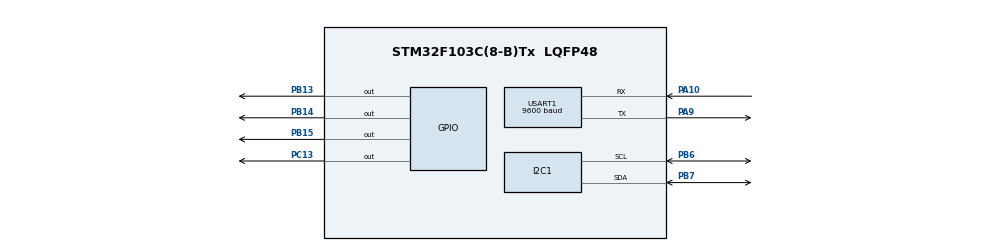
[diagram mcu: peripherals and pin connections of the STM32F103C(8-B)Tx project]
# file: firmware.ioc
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Mcu.Family=STM32F1
Mcu.Name=STM32F103C(8-B)Tx
Mcu.Package=LQFP48
NVIC.PriorityGroup=NVIC_PRIORITYGROUP_4
PA10.Mode=Asynchronous
PA10.Signal=USART1_RX
PA13.Mode=Serial_Wire
PA13.Signal=SYS_JTMS-SWDIO
PA14.Mode=Serial_Wire
PA14.Signal=SYS_JTCK-SWCLK
PA9.Mode=Asynchronous
PA9.Signal=USART1_TX
PB13.Signal=GPIO_Output
PB14.Signal=GPIO_Output
PB15.Signal=GPIO_Output
PB6.Mode=I2C
PB6.Signal=I2C1_SCL
PB7.Mode=I2C
PB7.Signal=I2C1_SDA
PC13-TAMPER-RTC.Signal=GPIO_Output
PC14-OSC32_IN.Mode=LSE-External-Oscillator
PC14-OSC32_IN.Signal=RCC_OSC32_IN
PC15-OSC32_OUT.Mode=LSE-External-Oscillator
PC15-OSC32_OUT.Signal=RCC_OSC32_OUT
PD0-OSC_IN.Mode=HSE-External-Oscillator
PD0-OSC_IN.Signal=RCC_OSC_IN
PD1-OSC_OUT.Mode=HSE-External-Oscillator
PD1-OSC_OUT.Signal=RCC_OSC_OUT
ProjectManager.HeapSize=0x200
ProjectManager.StackSize=0x400
ProjectManager.TargetToolchain=STM32CubeIDE
RCC.AHBFreq_Value=72000000
RCC.APB1CLKDivider=RCC_HCLK_DIV2
RCC.APB1Freq_Value=36000000
RCC.APB1TimFreq_Value=72000000
RCC.APB2Freq_Value=72000000
RCC.APB2TimFreq_Value=72000000
RCC.HCLKFreq_Value=72000000
RCC.PLLMUL=RCC_PLL_MUL9
RCC.PLLSourceVirtual=RCC_PLLSOURCE_HSE
RCC.SYSCLKFreq_VALUE=72000000
RCC.SYSCLKSource=RCC_SYSCLKSOURCE_PLLCLK
RCC.USBFreq_Value=72000000
USART1.BaudRate=9600
USART1.Parity=PARITY_EVEN
USART1.VirtualMode=VM_ASYNC
USART1.WordLength=WORDLENGTH_9B
board=custom

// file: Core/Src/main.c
/* USER CODE BEGIN Header */
/**
 ******************************************************************************
 * @file           : main.c
 * @brief          : Main program body
 ******************************************************************************
 * @attention
 *
 * <h2><center>&copy; Copyright (c) 2019 STMicroelectronics.
 * All rights reserved.</center></h2>
 *
 * This software component is licensed by ST under BSD 3-Clause license,
 * the "License"; You may not use this file except in compliance with the
 * License. You may obtain a copy of the License at:
 *                        opensource.org/licenses/BSD-3-Clause
 *
 ******************************************************************************
 */
/* USER CODE END Header */

#include "main.h"

/* USER CODE BEGIN PD */
#define RESET GPIO_PIN_13
#define BOOT0 GPIO_PIN_15
#define BOOT1 GPIO_PIN_14
/* USER CODE END PD */

I2C_HandleTypeDef hi2c1;

UART_HandleTypeDef huart1;

/* USER CODE BEGIN PV */
UART_HandleTypeDef huart1;
int initialize= 0x71u;
uint8_t UCack;
uint8_t positive_ack=0x79;
uint8_t negative_ack=0xF1;
uint8_t version;
uint8_t commands[11];
uint8_t option1;
uint8_t option2;
uint8_t id[2];
uint8_t pages[2]={0x00,0x01};
uint8_t number_of_pages=0x01;
uint32_t length=2000;//20 in decimal
//uint8_t firmware[2000];
uint8_t read_address=0xa0;
uint8_t write_address=0xa1;
uint8_t read;
/* USER CODE END PV */

void SystemClock_Config(void);
static void MX_GPIO_Init(void);
static void MX_I2C1_Init(void);
static void MX_USART1_UART_Init(void);
/* USER CODE BEGIN PFP */
void send(uint8_t address);
uint8_t recieve();
int start();
int getversion();
int get_version_and_read_protection_status();
int get_id();
int read_memory(uint32_t address, uint8_t number_of_bytes,uint16_t start );
uint8_t get_checksum(uint32_t address);
void send_address(uint32_t address);
int go(uint32_t address);
int write(uint32_t address,uint8_t length,uint16_t start);
int write_unprotected();
int erase(uint8_t num_of_pages);
void restart();
int write_algorithm(uint32_t length);
void firmware_update(uint32_t length);
int get_backup(uint32_t length);

void make_array();
int EEPROM_init();
int EEPROM_write(uint16_t address,uint8_t data);
uint8_t EEPROM_read(uint16_t address);
/* USER CODE END PFP */

int main(void)
{

  /* MCU Configuration--------------------------------------------------------*/

  /* Reset of all peripherals, Initializes the Flash interface and the Systick. */
  HAL_Init();

  /* Configure the system clock */
  SystemClock_Config();

  /* Initialize all configured peripherals */
  MX_GPIO_Init();
  MX_I2C1_Init();
  MX_USART1_UART_Init();
  /* USER CODE BEGIN 2 */
	//  HAL_UART_Transmit(&huart1,(uint8_t*)(0xF7), 1, 10);
	//  HAL_UART_Transmit(&huart1,(uint8_t*)(0xF7), 1, 10);
	//  HAL_Delay(100);
	//  HAL_UART_Receive(&huart1,&UCack, 1,10);
	//  if(UCack==0x79){
	//	  HAL_GPIO_TogglePin(GPIOC, GPIO_PIN_13);
	//
	//  }
  /* USER CODE END 2 */

  /* Infinite loop */
  /* USER CODE BEGIN WHILE */
//  	restart();
//	start();
//	go(0x08000004);
//	//erase(number_of_pages);
//	HAL_Delay(50);
//	//start();
//	restart();
//	start();
//	write(0x08000230,0xf);
  //restart();
//  HAL_Delay(100);
//  restart();
//  while(!start()){
//	  restart();
//  }
  HAL_Delay(100);
  while(!(EEPROM_init()));
//  for(uint16_t address=0x00;address<=0xff;address=address+1){
//	  HAL_GPIO_TogglePin(GPIOC, GPIO_PIN_13);
//	  HAL_Delay(10);
//	  if(HAL_I2C_IsDeviceReady(&hi2c1,0xA0,1,5)==HAL_OK){
//		  while(1){
//		  HAL_GPIO_TogglePin(GPIOC, GPIO_PIN_13);
//		  HAL_Delay(1000);
//		  }
//	  	}
//  }
//  EEPROM_write(0xff,0x34);
//  EEPROM_write(0x1ff,0xDD);
//  for(uint16_t address=0x00;address<=0x4ff;address=address+1){
//	  while(!(EEPROM_write(address,address%128)));
//	  HAL_GPIO_TogglePin(GPIOC, GPIO_PIN_13);
//	  HAL_Delay(25);
//  }
//  read= EEPROM_read(0x03);
//  read= EEPROM_read(0xffff);
//  make_array();
//  restart();
//  start();
//  firmware_update(0x8000);

  //restart();

//  HAL_Delay(100);
//  firmware_update(0x400);
//  get_backup(0x400);
//  firmware_update(0x400);
//  get_backup(0x400);

  //firmware_update(0x50);
  //go(0x08000004);
	//  getversion();
	//  get_version_and_read_protection_status();
	//  get_id();
	//  read_memory(0x08000000, 0xff);
  	//firmware_update(0x8000);
    //while(!EEPROM_write(0x00,0x00));
   	//get_backup(0x8000);
   	firmware_update(0x8000);
	while (1)
	{
//		HAL_GPIO_TogglePin(GPIOC, GPIO_PIN_13);
//		HAL_Delay(25);
//		get_backup(0x10);
//		for(uint16_t address=0x00;address<=0x8000;address=address+1){
//			send(EEPROM_read(address));
//		}
		//HAL_Delay(100);
//		firmware_update(0x400);

		//HAL_Delay(500);
//		firmware_update(0x400);

//		HAL_GPIO_TogglePin(GPIOC, GPIO_PIN_13);
		//HAL_Delay(500);
		//	 if((USART1->SR & USART_SR_RXNE)){
		//		 char data=USART1->DR;
		//		 USART1->DR=data;
		//		 while(!(USART1->SR & USART_SR_TC));
		//	 }
    /* USER CODE END WHILE */

	}
}

void SystemClock_Config(void)
{
  RCC_OscInitTypeDef RCC_OscInitStruct = {0};
  RCC_ClkInitTypeDef RCC_ClkInitStruct = {0};

  /** Initializes the CPU, AHB and APB busses clocks
  */
  RCC_OscInitStruct.OscillatorType = RCC_OSCILLATORTYPE_HSI;
  RCC_OscInitStruct.HSIState = RCC_HSI_ON;
  RCC_OscInitStruct.HSICalibrationValue = RCC_HSICALIBRATION_DEFAULT;
  RCC_OscInitStruct.PLL.PLLState = RCC_PLL_NONE;
  if (HAL_RCC_OscConfig(&RCC_OscInitStruct) != HAL_OK)
  {
    Error_Handler();
  }
  /** Initializes the CPU, AHB and APB busses clocks
  */
  RCC_ClkInitStruct.ClockType = RCC_CLOCKTYPE_HCLK|RCC_CLOCKTYPE_SYSCLK
                              |RCC_CLOCKTYPE_PCLK1|RCC_CLOCKTYPE_PCLK2;
  RCC_ClkInitStruct.SYSCLKSource = RCC_SYSCLKSOURCE_HSI;
  RCC_ClkInitStruct.AHBCLKDivider = RCC_SYSCLK_DIV1;
  RCC_ClkInitStruct.APB1CLKDivider = RCC_HCLK_DIV2;
  RCC_ClkInitStruct.APB2CLKDivider = RCC_HCLK_DIV1;

  if (HAL_RCC_ClockConfig(&RCC_ClkInitStruct, FLASH_LATENCY_0) != HAL_OK)
  {
    Error_Handler();
  }
}

static void MX_I2C1_Init(void)
{

  hi2c1.Instance = I2C1;
  hi2c1.Init.ClockSpeed = 400000;
  hi2c1.Init.DutyCycle = I2C_DUTYCYCLE_2;
  hi2c1.Init.OwnAddress1 = 0;
  hi2c1.Init.AddressingMode = I2C_ADDRESSINGMODE_7BIT;
  hi2c1.Init.DualAddressMode = I2C_DUALADDRESS_DISABLE;
  hi2c1.Init.OwnAddress2 = 0;
  hi2c1.Init.GeneralCallMode = I2C_GENERALCALL_DISABLE;
  hi2c1.Init.NoStretchMode = I2C_NOSTRETCH_DISABLE;
  if (HAL_I2C_Init(&hi2c1) != HAL_OK)
  {
    Error_Handler();
  }

}

static void MX_USART1_UART_Init(void)
{

  huart1.Instance = USART1;
  huart1.Init.BaudRate = 115200;
  huart1.Init.WordLength = UART_WORDLENGTH_9B;
  huart1.Init.StopBits = UART_STOPBITS_1;
  huart1.Init.Parity = UART_PARITY_EVEN;
  huart1.Init.Mode = UART_MODE_TX_RX;
  huart1.Init.HwFlowCtl = UART_HWCONTROL_NONE;
  huart1.Init.OverSampling = UART_OVERSAMPLING_16;
  if (HAL_UART_Init(&huart1) != HAL_OK)
  {
    Error_Handler();
  }

}

static void MX_GPIO_Init(void)
{
  GPIO_InitTypeDef GPIO_InitStruct = {0};

  /* GPIO Ports Clock Enable */
  __HAL_RCC_GPIOC_CLK_ENABLE();
  __HAL_RCC_GPIOD_CLK_ENABLE();
  __HAL_RCC_GPIOB_CLK_ENABLE();
  __HAL_RCC_GPIOA_CLK_ENABLE();

  /*Configure GPIO pin Output Level */
  HAL_GPIO_WritePin(GPIOC, GPIO_PIN_13, GPIO_PIN_RESET);

  /*Configure GPIO pin Output Level */
  HAL_GPIO_WritePin(GPIOB, GPIO_PIN_13|GPIO_PIN_14|GPIO_PIN_15, GPIO_PIN_RESET);

  /*Configure GPIO pin : PC13 */
  GPIO_InitStruct.Pin = GPIO_PIN_13;
  GPIO_InitStruct.Mode = GPIO_MODE_OUTPUT_PP;
  GPIO_InitStruct.Pull = GPIO_NOPULL;
  GPIO_InitStruct.Speed = GPIO_SPEED_FREQ_LOW;
  HAL_GPIO_Init(GPIOC, &GPIO_InitStruct);

  /*Configure GPIO pins : PB13 PB14 PB15 */
  GPIO_InitStruct.Pin = GPIO_PIN_13|GPIO_PIN_14|GPIO_PIN_15;
  GPIO_InitStruct.Mode = GPIO_MODE_OUTPUT_PP;
  GPIO_InitStruct.Pull = GPIO_NOPULL;
  GPIO_InitStruct.Speed = GPIO_SPEED_FREQ_LOW;
  HAL_GPIO_Init(GPIOB, &GPIO_InitStruct);

}

/* USER CODE BEGIN 4 */
void send(uint8_t address){
	USART1->DR=address;
	while(!(USART1->SR & USART_SR_TC));

}
uint8_t recieve(){
	while(!(USART1->SR & USART_SR_RXNE));
	uint8_t data=USART1->DR;
	return data;
}
uint8_t get_checksum(uint32_t address){
	uint8_t byte_1 = (address & 0xff000000) >> 24;
	uint8_t byte_2 = (address & 0x00ff0000) >> 16;
	uint8_t byte_3 = (address & 0x0000ff00) >> 8;
	uint8_t byte_4 = (address & 0x000000ff);
	uint8_t check_sum= byte_1^byte_2^byte_3^byte_4;

	return check_sum;

}
void send_address(uint32_t address){
	uint8_t byte = (address & 0xff000000) >> 24;
	send(byte);
	byte = (address & 0x00ff0000) >> 16;
	send(byte);
	byte= (address & 0x0000ff00) >> 8;
	send(byte);
	byte = (address & 0x000000ff);
	send(byte);
}
int start(){
	send(0x7F);
	if(recieve()==positive_ack){
		return 1;
		//HAL_UART_Transmit(&huart1, (uint8_t*)("Boot loader mode"), 25, 100);
	}
	HAL_GPIO_TogglePin(GPIOC, GPIO_PIN_13);
	HAL_Delay(10);
	return 0;
}
int getversion(){
	uint8_t state=0x00;
	uint8_t number_of_bytes;
	while(1){
		switch (state)
		{
		case 0x01:
			number_of_bytes=recieve();
			//duplicate=number_of_bytes;
			uint8_t counter=0x00;
			while(counter<=number_of_bytes){
				if(counter==0x00){
					version=recieve();
				}else{
					commands[counter]=recieve();
				}
				counter=counter+0x01;
			}
			state=0x02;
			;
		case 0x02:
			if(positive_ack==recieve()){
				return 1;
			}else{
				return 0;
			}
			;
		default:
			send(0x00);
			send(0xff);
			if(recieve()==positive_ack){
				state=0x01;
			}else{
				return 0;
			}
			;
		}
	}
}

int get_version_and_read_protection_status(){
	uint8_t state=0x00;
	while(1){
		switch (state)
		{
		case 0x01:
			version=recieve();
			option1=recieve();
			option2=recieve();
			if(positive_ack==recieve()){
				return 1;
			}else{
				return -1;
			}
			;
		default:
			send(0x01);
			send(0xfe);
			if(recieve()==positive_ack){
				state=0x01;
			}else{
				return -1;
			}
			;
		}
	}
}
int get_id(){
	uint8_t state=0x00;
	uint8_t number_of_bytes=0x00;
	while(1){
		switch (state)
		{
		case 0x01:
			number_of_bytes=recieve();
			//duplicate=number_of_bytes;
			uint8_t counter=0x00;
			while(counter<=number_of_bytes){
				id[counter]=recieve();
				counter=counter+0x01;
			}
			state=0x02;
			;
		case 0x02:
			if(positive_ack==recieve()){
				return 1;
			}else{
				return -1;
			}
			;
		default:
			send(0x02);
			send(0xfd);
			if(recieve()==positive_ack){
				state=0x01;
			}else{
				return -1;
			}
			;
		}
	}
}
int read_memory(uint32_t address, uint8_t number_of_bytes,uint16_t start){
	uint8_t state=0x00;
	uint16_t counter=0x00;
	uint8_t buffer[256];
	while(1){
		switch (state)
		{
		case 0x01:
			send_address(address);
			send(get_checksum(address));
			//duplicate=number_of_bytes;
			if(positive_ack==recieve()){
				state=0x02;
			}else {
				return 0;
			}
			;
		case 0x02:
			send(number_of_bytes);
			send(~(number_of_bytes));
			if(positive_ack==recieve()){
				while(number_of_bytes>=counter){
					buffer[counter]=recieve();
					counter=counter+0x01;
				}
				counter=0x00;
				while(number_of_bytes>=counter){
					EEPROM_write(start, buffer[counter]);
					counter=counter+0x01;
					start=start+0x01;
				}
				return 1;
			}else{
				return 0;
			}
			;
		case 0x03:
			while(number_of_bytes>=counter){
				recieve();
				counter=counter+0x01;
			}
			counter=0x00;
			while(number_of_bytes>=counter){
				EEPROM_write(start, buffer[counter]);
				counter=counter+0x01;
				start=start+0x01;
			}
			return 1;
			;
		default:
			send(0x11);
			send(0xEE);
			if(recieve()==positive_ack){
				state=0x01;
			}else{
				return -1;
			}
			;
		}
	}

}

int go(uint32_t address){
	uint8_t state=0x00;
	while(1){
		switch (state)
		{
		case 0x01:
			send_address(address-0x04);
			send(get_checksum(address-0x04));
			if(positive_ack==recieve()){
				return 1;
			}else{
				return -1;
			}
			;
		default:
			send(0x21);
			send(0xde);
			if(recieve()==positive_ack){
				state=0x01;
			}else{
				return -1;
			}
			;
		}
	}

}
int write(uint32_t address,uint8_t length,uint16_t start){
	uint8_t state=0x00;
	uint16_t counter=0x00;
	uint8_t check_sum;
	uint8_t temp;
	while(1){
		switch (state)
		{
		case 0x01:
			send_address(address);
			send(get_checksum(address));
			if(positive_ack==recieve()){
				state=0x02;
			}else{
				return -1;
			}
			;
		case 0x02:
			send(length);
			check_sum=length;
			while(length>=counter){
				temp=EEPROM_read(start);
				send(temp);
				check_sum=check_sum ^temp ;
				counter=counter+1;
				start=start+1;
			}
			send(check_sum);
			state=0x03;
			;
		case 0x03:
			if(recieve()==positive_ack){
				return 1;
			}else{
				return -1;
			}
			;
		default:
			send(0x31);
			send(0xce);
			if(recieve()==positive_ack){
				state=0x01;
			}else{
				return -1;
			}
			;
		}
	}

}
int write_unprotected(){
	uint8_t state=0x00;
	while(1){
		switch (state)
		{
		case 0x01:
			if(positive_ack==recieve()){
				return 1;
			}else{
				return 0;
			}
			;
		default:
			send(0x73);
			send(0x8c);
			if(recieve()==positive_ack){
				state=0x01;
			}else{
				return 0;
			}
			;
		}
	}
}
int erase(uint8_t num_of_pages){
	uint8_t state=0x00;
	uint8_t check_sum=num_of_pages;
	uint8_t counter=0x00;
	while(1){
		switch (state)
		{
		case 0x01:
			send(num_of_pages);
			while(counter<=num_of_pages){
				send(counter);
				check_sum=check_sum ^ counter;
				counter=counter+1;
			}
			send(check_sum);
			if(recieve()==positive_ack){
				return 1;
			}else{
				return 0;
			}
			;
		default:
			send(0x43);
			send(0xbc);
			if(recieve()==positive_ack){
				state=0x01;
			}else{
				return 0;
			}
			;
		}
	}
}
void restart(){
  	HAL_GPIO_WritePin(GPIOB, GPIO_PIN_13, GPIO_PIN_RESET);
  	HAL_GPIO_WritePin(GPIOB, GPIO_PIN_15, GPIO_PIN_SET);
  	HAL_GPIO_WritePin(GPIOB,GPIO_PIN_14, GPIO_PIN_RESET);
  	HAL_Delay(10);

  	HAL_GPIO_WritePin(GPIOB, GPIO_PIN_13, GPIO_PIN_SET);
  	HAL_Delay(10);
}
void firmware_update(uint32_t length){
	uint8_t erase_pages=(length/1024);
	if (length%1024>0){
		erase_pages=erase_pages+0x01;
	}
	erase_pages=erase_pages-0x01;

	//// erase the pages
	restart();

	HAL_Delay(100);

	while(!start()){
		restart();
	}

	HAL_Delay(100);
	while(!erase(erase_pages)){
		restart();
		while(!start());
	}
	//// erase the pages
	HAL_Delay(100);
	/// write the pages
	//restart();

	//HAL_Delay(10);

	while(!write_algorithm(length)){
		restart();
		while(!start());
	}

	/// write the pages

	go(0x8000004);
}

int  get_backup(uint32_t length){
	int read_times=(length/256);
	uint16_t start_1=0;
	uint32_t address=0x08000000;
	int status;
	if (length%256>0){
		read_times=read_times+0x01;
	}
	read_times=read_times-0x01;

	restart();
	HAL_Delay(100);

	while(!start()){
			restart();
		}
	HAL_Delay(100);

	while(read_times>=0){
		if(read_times==0){
			status=read_memory(address,length-1,start_1);
			if(status==0){
				return 0;
			}
		}else{
			status=read_memory(address,0xff,start_1);
			if(status==0){
				return 0;
			}
			start_1=start_1+0x100;
			length=length-0x100;
			address=address+0x100;
		}
		read_times=read_times-0x01;

	}

	return 1;
	//// erase the pages

}

int write_algorithm(uint32_t length){
	int count=length/256;
	int status;
	if(length%256>0){
		count=count+1;
	}
	uint16_t start=0;
	uint32_t address=0x08000000;
	while(count>0){
		if(count==1){
			status=write(address,length-1,start);
			if(!status){
				return 0;
			}
		}else{
			status=write(address,0xff,start);
			if(!status){
				return 0;
			}
			start=start+0x100;
			length=length-0x100;
			address=address+0x100;
			HAL_Delay(20); // there should be a delay
		}
		count=count-1;
		}
	return 1;
}
void make_array(){
	for(int i=0;i<2000;i++){
//		firmware[i]=i%128;
	}
}
int EEPROM_init(){
	if(HAL_I2C_IsDeviceReady(&hi2c1,0xA0,1,5)==HAL_OK){
		return 1;
	}else{
		return 0;
	}
}
int EEPROM_write(uint16_t address,uint8_t data){
	uint8_t address_data[3]={(address & 0xff00) >> 8,address & 0x00ff,data};
	uint8_t correct;

	HAL_I2C_Master_Transmit(&hi2c1,(uint16_t)0xA0,address_data, 3, 100);// write to
	HAL_Delay(5);

//	correct=EEPROM_read(address);
//	if(correct==data){
//		return 1;
//	}

	return 1;
}

uint8_t EEPROM_read(uint16_t address){
	uint8_t _address[2]={(address & 0xff00) >> 8,address & 0x00ff};
	uint8_t read;

	HAL_I2C_Master_Transmit(&hi2c1,(uint16_t)0xA0,_address,2,100);
	HAL_I2C_Master_Receive(&hi2c1,(uint16_t)0xA0, &read,1, 100);

//	HAL_GPIO_TogglePin(GPIOC, GPIO_PIN_13);
//	HAL_Delay(10);

	return read;

}
/* USER CODE END 4 */

void Error_Handler(void)
{
}

/************************ (C) COPYRIGHT STMicroelectronics *****END OF FILE****/
